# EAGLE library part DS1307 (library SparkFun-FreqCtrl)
I2C real-time clock with battery backup.

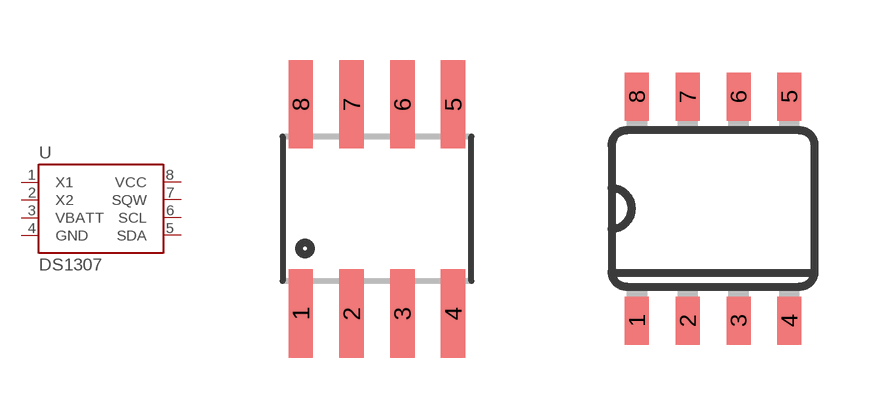
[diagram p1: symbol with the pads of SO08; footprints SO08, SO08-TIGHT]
Designator prefix -

## DS1307SO8  [SO08]
1  X1
2  X2
3  VBATT
4  GND
5  SDA
6  SCL
7  SQW
8  VCC

## DS1307SO8-TIGHT (PROD_ID: IC-08138)  [SO08-TIGHT]
Pads as for SO08

## Footprint SO08 (pad centres in mm)
Small Outline Package Fits JEDEC packages (narrow SOIC-8)
smd 0.61 x 2.21: 1 -1.905,-2.616; 2 -0.635,-2.616; 3 0.635,-2.616; 4 1.905,-2.616; 5 1.905,2.616; 6 0.635,2.616; 7 -0.635,2.616; 8 -1.905,2.616

## Footprint SO08-TIGHT (pad centres in mm)
smd 0.6 x 1.2: 1 -1.905,-2.8; 2 -0.635,-2.8; 3 0.635,-2.8; 4 1.905,-2.8; 5 1.905,2.8; 6 0.635,2.8; 7 -0.635,2.8; 8 -1.905,2.8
